VERSION 5.7 ;
  NOWIREEXTENSIONATPIN ON ;
  DIVIDERCHAR "/" ;
  BUSBITCHARS "[]" ;
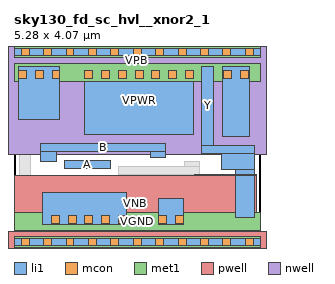
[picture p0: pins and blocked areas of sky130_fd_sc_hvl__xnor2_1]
MACRO sky130_fd_sc_hvl__xnor2_1
  CLASS BLOCK ;
  FOREIGN sky130_fd_sc_hvl__xnor2_1 ;
  ORIGIN 0.000 0.000 ;
  SIZE 5.280 BY 4.070 ;
  PIN A
    ANTENNAGATEAREA 2.250000 ;
    PORT
      LAYER li1 ;
        RECT 1.085 1.580 2.060 1.750 ;
    END
  END A
  PIN B
    ANTENNAGATEAREA 2.250000 ;
    PORT
      LAYER li1 ;
        RECT 1.565 2.100 3.255 2.120 ;
        RECT 0.575 1.930 3.255 2.100 ;
        RECT 0.575 1.725 0.905 1.930 ;
        RECT 2.925 1.805 3.255 1.930 ;
    END
  END B
  PIN VGND
    USE GROUND ;
    PORT
      LAYER li1 ;
        RECT 0.610 0.365 2.410 1.050 ;
        RECT 3.100 0.365 3.630 0.925 ;
      LAYER mcon ;
        RECT 0.800 0.395 0.970 0.565 ;
        RECT 1.160 0.395 1.330 0.565 ;
        RECT 1.520 0.395 1.690 0.565 ;
        RECT 1.880 0.395 2.050 0.565 ;
        RECT 2.240 0.395 2.410 0.565 ;
        RECT 3.100 0.395 3.270 0.565 ;
        RECT 3.460 0.395 3.630 0.565 ;
      LAYER met1 ;
        RECT 0.000 0.255 5.280 0.625 ;
    END
  END VGND
  PIN VNB
    ANTENNADIFFAREA 0.897600 ;
    PORT
      LAYER pwell ;
        RECT 3.860 1.415 5.190 1.455 ;
        RECT 0.020 0.215 5.190 1.415 ;
        RECT -0.130 -0.215 5.410 0.215 ;
      LAYER li1 ;
        RECT 0.000 -0.085 5.280 0.085 ;
      LAYER mcon ;
        RECT 0.155 -0.085 0.325 0.085 ;
        RECT 0.635 -0.085 0.805 0.085 ;
        RECT 1.115 -0.085 1.285 0.085 ;
        RECT 1.595 -0.085 1.765 0.085 ;
        RECT 2.075 -0.085 2.245 0.085 ;
        RECT 2.555 -0.085 2.725 0.085 ;
        RECT 3.035 -0.085 3.205 0.085 ;
        RECT 3.515 -0.085 3.685 0.085 ;
        RECT 3.995 -0.085 4.165 0.085 ;
        RECT 4.475 -0.085 4.645 0.085 ;
        RECT 4.955 -0.085 5.125 0.085 ;
      LAYER met1 ;
        RECT 0.000 -0.115 5.280 0.115 ;
    END
  END VNB
  PIN VPB
    ANTENNADIFFAREA 0.897600 ;
    PORT
      LAYER nwell ;
        RECT -0.330 1.885 5.610 4.485 ;
      LAYER li1 ;
        RECT 0.000 3.985 5.280 4.155 ;
      LAYER mcon ;
        RECT 0.155 3.985 0.325 4.155 ;
        RECT 0.635 3.985 0.805 4.155 ;
        RECT 1.115 3.985 1.285 4.155 ;
        RECT 1.595 3.985 1.765 4.155 ;
        RECT 2.075 3.985 2.245 4.155 ;
        RECT 2.555 3.985 2.725 4.155 ;
        RECT 3.035 3.985 3.205 4.155 ;
        RECT 3.515 3.985 3.685 4.155 ;
        RECT 3.995 3.985 4.165 4.155 ;
        RECT 4.475 3.985 4.645 4.155 ;
        RECT 4.955 3.985 5.125 4.155 ;
      LAYER met1 ;
        RECT 0.000 3.955 5.280 4.185 ;
    END
  END VPB
  PIN VPWR
    USE POWER ;
    PORT
      LAYER li1 ;
        RECT 0.090 2.630 0.985 3.755 ;
        RECT 1.515 2.300 3.845 3.755 ;
        RECT 4.465 2.255 5.055 3.755 ;
      LAYER mcon ;
        RECT 0.095 3.505 0.265 3.675 ;
        RECT 0.455 3.505 0.625 3.675 ;
        RECT 0.815 3.505 0.985 3.675 ;
        RECT 1.515 3.505 1.685 3.675 ;
        RECT 1.875 3.505 2.045 3.675 ;
        RECT 2.235 3.505 2.405 3.675 ;
        RECT 2.595 3.505 2.765 3.675 ;
        RECT 2.955 3.505 3.125 3.675 ;
        RECT 3.315 3.505 3.485 3.675 ;
        RECT 3.675 3.505 3.845 3.675 ;
        RECT 4.495 3.505 4.665 3.675 ;
        RECT 4.855 3.505 5.025 3.675 ;
      LAYER met1 ;
        RECT 0.000 3.445 5.280 3.815 ;
    END
  END VPWR
  PIN Y
    ANTENNADIFFAREA 1.481250 ;
    PORT
      LAYER li1 ;
        RECT 4.025 2.075 4.275 3.755 ;
        RECT 4.025 1.905 5.155 2.075 ;
        RECT 4.445 1.545 5.155 1.905 ;
        RECT 4.750 0.535 5.155 1.545 ;
    END
  END Y
  OBS
      LAYER li1 ;
        RECT 1.165 2.450 1.335 3.755 ;
        RECT 0.110 2.280 1.335 2.450 ;
        RECT 0.110 1.400 0.360 2.280 ;
        RECT 3.650 1.625 3.980 1.725 ;
        RECT 2.240 1.455 3.980 1.625 ;
        RECT 2.240 1.400 2.410 1.455 ;
        RECT 0.110 1.230 2.410 1.400 ;
        RECT 0.110 0.495 0.440 1.230 ;
        RECT 2.590 1.105 4.300 1.285 ;
        RECT 2.590 0.495 2.920 1.105 ;
        RECT 3.970 0.535 4.300 1.105 ;
  END
END sky130_fd_sc_hvl__xnor2_1
END LIBRARY

